VERSION 5.8 ;
BUSBITCHARS "[]" ;
DIVIDERCHAR "/" ;
UNITS
  DATABASE MICRONS 1000 ;
END UNITS
MANUFACTURINGGRID 0.005 ;

# Synthetic stack for the PRL two-sides spacing pre-screen tests. Every name and value is
# invented. V1 states the reference's Figure 2-155 rule (class VA to VA) and a rule naming a class
# the layer does not define; V2 states one rule under the property name of the reference's syntax
# summary (one S).

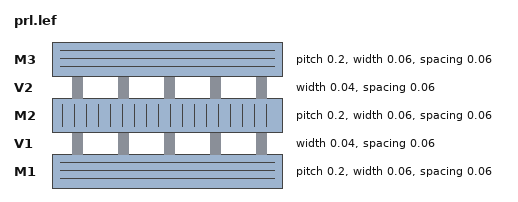
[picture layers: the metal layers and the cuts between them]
LAYER M1
  TYPE ROUTING ;
  DIRECTION HORIZONTAL ;
  PITCH 0.2 ;
  WIDTH 0.06 ;
  SPACING 0.06 ;
END M1

LAYER V1
  TYPE CUT ;
  WIDTH 0.04 ;
  SPACING 0.06 ;
  PROPERTY LEF58_CUTCLASS "CUTCLASS VA WIDTH 0.04 ; CUTCLASS VB WIDTH 0.04 LENGTH 0.08 ;" ;
  PROPERTY LEF58_PRLTWOSIDESSPACING "
    PRLTWOSIDESSPACING 0.15 0.2 CUTCLASS VA TO VA PRL -0.07 -0.05 -0.1 -0.08 ;
    PRLTWOSIDESSPACING 0.15 0.2 CUTCLASS VA TO VC PRL -0.07 -0.05 -0.1 -0.08 ; " ;
END V1

LAYER M2
  TYPE ROUTING ;
  DIRECTION VERTICAL ;
  PITCH 0.2 ;
  WIDTH 0.06 ;
  SPACING 0.06 ;
END M2

LAYER V2
  TYPE CUT ;
  WIDTH 0.04 ;
  SPACING 0.06 ;
  PROPERTY LEF58_CUTCLASS "CUTCLASS VA WIDTH 0.04 ;" ;
  PROPERTY LEF58_PRLTWOSIDESPACING "PRLTWOSIDESSPACING 0.15 0.2 CUTCLASS VA TO VA PRL -0.07 -0.05 -0.1 -0.08 ;" ;
END V2

LAYER M3
  TYPE ROUTING ;
  DIRECTION HORIZONTAL ;
  PITCH 0.2 ;
  WIDTH 0.06 ;
  SPACING 0.06 ;
END M3

VIA VA12 DEFAULT
  LAYER M1 ;
    RECT -0.03 -0.03 0.03 0.03 ;
  LAYER V1 ;
    RECT -0.02 -0.02 0.02 0.02 ;
  LAYER M2 ;
    RECT -0.03 -0.03 0.03 0.03 ;
END VA12

VIA VB12 DEFAULT
  LAYER M1 ;
    RECT -0.03 -0.05 0.03 0.05 ;
  LAYER V1 ;
    RECT -0.02 -0.04 0.02 0.04 ;
  LAYER M2 ;
    RECT -0.03 -0.05 0.03 0.05 ;
END VB12

END LIBRARY
